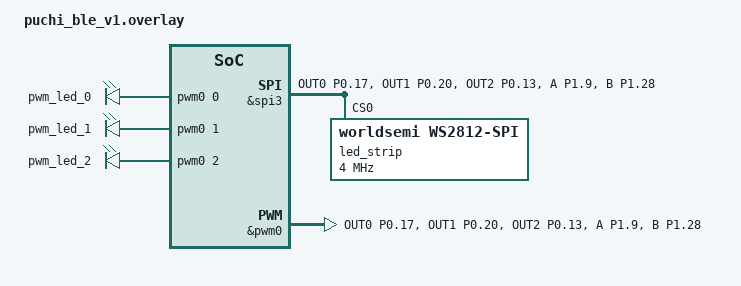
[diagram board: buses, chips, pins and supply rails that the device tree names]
#include <dt-bindings/led/led.h>

&pinctrl {
    // backlight
    spi3_default: spi3_default { {
        group1 {
            psels = <NRF_PSEL(PWM_OUT0, 0, 17)>,
                    <NRF_PSEL(PWM_OUT1, 0, 20)>,
                    <NRF_PSEL(PWM_OUT2, 0, 13)>;
        };
    };
    spi3_sleep: spi3_sleep {
        group1 {
            psels = <NRF_PSEL(PWM_OUT0, 0, 17)>,
                    <NRF_PSEL(PWM_OUT1, 0, 20)>,
                    <NRF_PSEL(PWM_OUT2, 0, 13)>;
            low-power-enable;
        };
    };
    // encoder driver
    qdec_default: qdec_default {
        group1 {
            psels = <NRF_PSEL(QDEC_A, 1, 9)>,
                    <NRF_PSEL(QDEC_B, 1, 28)>;
            bias-pull-up;
        };
    };
	&spi3 {
    compatible = "nordic,nrf-spim";
    status = "okay";

    pinctrl-0 = <&spi3_default>;
    pinctrl-1 = <&spi3_sleep>;
    pinctrl-names = "default", "sleep";

    led_strip: ws2812@0 {
        compatible = "worldsemi,ws2812-spi";
        // label = "WS2812";

        /* SPI */
        reg = <0>; /* ignored, but necessary for SPI bindings */
        spi-max-frequency = <4000000>;

        /* WS2812 */
        chain-length = <10>; /* arbitrary; change at will */
        spi-one-frame = <0x70>;
        spi-zero-frame = <0x40>;

        color-mapping = <LED_COLOR_ID_GREEN LED_COLOR_ID_RED LED_COLOR_ID_BLUE>;
    };
};

/ {
    backlight: pwmleds {
        compatible = "pwm-leds";
        label = "Backlight LEDs";
        pwm_led_0: pwm_led_0 {
            pwms = <&pwm0 0 PWM_MSEC(10) PWM_POLARITY_NORMAL>;
        };
        pwm_led_1: pwm_led_1 {
            pwms = <&pwm0 1 PWM_MSEC(10) PWM_POLARITY_NORMAL>;
        };
        pwm_led_2: pwm_led_2 {
            pwms = <&pwm0 2 PWM_MSEC(10) PWM_POLARITY_NORMAL>;
        };
    };
};

&pwm0 {
    status = "okay";
    pinctrl-0 = <&spi3_default>;
    pinctrl-1 = <&spi3_sleep>;
    pinctrl-names = "default", "sleep";
};

/ {
	chosen {
		 zmk,backlight = &backlight;
	};
};
